# Generated by FakeRAM 2.0
VERSION 5.7 ;
BUSBITCHARS "[]" ;
PROPERTYDEFINITIONS
  MACRO width INTEGER ;
  MACRO depth INTEGER ;
  MACRO banks INTEGER ;
END PROPERTYDEFINITIONS
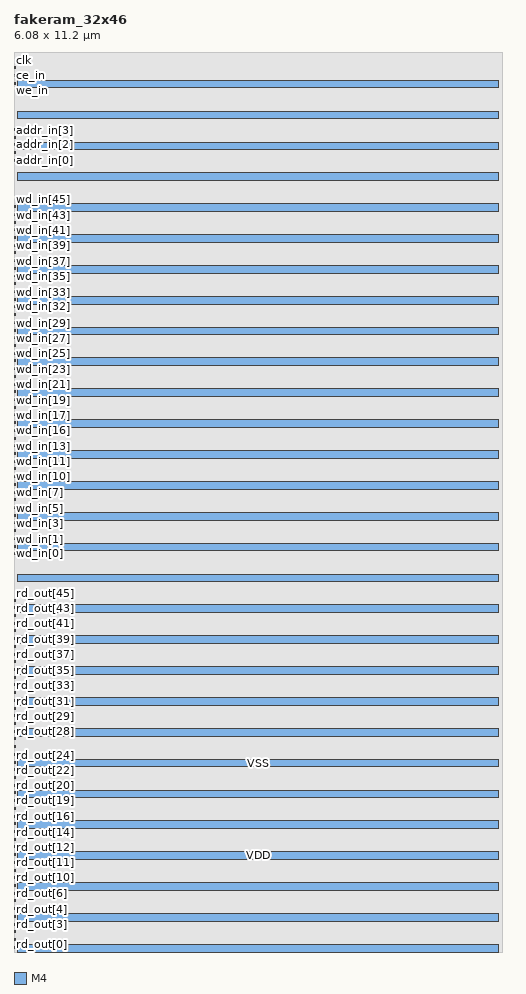
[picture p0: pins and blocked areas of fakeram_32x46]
MACRO fakeram_32x46
  PROPERTY width 46 ;
  PROPERTY depth 32 ;
  PROPERTY banks 1 ;
  FOREIGN fakeram_32x46 0 0 ;
  SYMMETRY X Y R90 ;
  SIZE 6.080 BY 11.200 ;
  CLASS BLOCK ;
  PIN rd_out[0]
    DIRECTION OUTPUT ;
    USE SIGNAL ;
    SHAPE ABUTMENT ;
    PORT
      LAYER M4 ;
      RECT 0.000 0.048 0.024 0.072 ;
    END
  END rd_out[0]
  PIN rd_out[1]
    DIRECTION OUTPUT ;
    USE SIGNAL ;
    SHAPE ABUTMENT ;
    PORT
      LAYER M4 ;
      RECT 0.000 0.144 0.024 0.168 ;
    END
  END rd_out[1]
  PIN rd_out[2]
    DIRECTION OUTPUT ;
    USE SIGNAL ;
    SHAPE ABUTMENT ;
    PORT
      LAYER M4 ;
      RECT 0.000 0.240 0.024 0.264 ;
    END
  END rd_out[2]
  PIN rd_out[3]
    DIRECTION OUTPUT ;
    USE SIGNAL ;
    SHAPE ABUTMENT ;
    PORT
      LAYER M4 ;
      RECT 0.000 0.336 0.024 0.360 ;
    END
  END rd_out[3]
  PIN rd_out[4]
    DIRECTION OUTPUT ;
    USE SIGNAL ;
    SHAPE ABUTMENT ;
    PORT
      LAYER M4 ;
      RECT 0.000 0.432 0.024 0.456 ;
    END
  END rd_out[4]
  PIN rd_out[5]
    DIRECTION OUTPUT ;
    USE SIGNAL ;
    SHAPE ABUTMENT ;
    PORT
      LAYER M4 ;
      RECT 0.000 0.528 0.024 0.552 ;
    END
  END rd_out[5]
  PIN rd_out[6]
    DIRECTION OUTPUT ;
    USE SIGNAL ;
    SHAPE ABUTMENT ;
    PORT
      LAYER M4 ;
      RECT 0.000 0.624 0.024 0.648 ;
    END
  END rd_out[6]
  PIN rd_out[7]
    DIRECTION OUTPUT ;
    USE SIGNAL ;
    SHAPE ABUTMENT ;
    PORT
      LAYER M4 ;
      RECT 0.000 0.720 0.024 0.744 ;
    END
  END rd_out[7]
  PIN rd_out[8]
    DIRECTION OUTPUT ;
    USE SIGNAL ;
    SHAPE ABUTMENT ;
    PORT
      LAYER M4 ;
      RECT 0.000 0.816 0.024 0.840 ;
    END
  END rd_out[8]
  PIN rd_out[9]
    DIRECTION OUTPUT ;
    USE SIGNAL ;
    SHAPE ABUTMENT ;
    PORT
      LAYER M4 ;
      RECT 0.000 0.912 0.024 0.936 ;
    END
  END rd_out[9]
  PIN rd_out[10]
    DIRECTION OUTPUT ;
    USE SIGNAL ;
    SHAPE ABUTMENT ;
    PORT
      LAYER M4 ;
      RECT 0.000 1.008 0.024 1.032 ;
    END
  END rd_out[10]
  PIN rd_out[11]
    DIRECTION OUTPUT ;
    USE SIGNAL ;
    SHAPE ABUTMENT ;
    PORT
      LAYER M4 ;
      RECT 0.000 1.104 0.024 1.128 ;
    END
  END rd_out[11]
  PIN rd_out[12]
    DIRECTION OUTPUT ;
    USE SIGNAL ;
    SHAPE ABUTMENT ;
    PORT
      LAYER M4 ;
      RECT 0.000 1.200 0.024 1.224 ;
    END
  END rd_out[12]
  PIN rd_out[13]
    DIRECTION OUTPUT ;
    USE SIGNAL ;
    SHAPE ABUTMENT ;
    PORT
      LAYER M4 ;
      RECT 0.000 1.296 0.024 1.320 ;
    END
  END rd_out[13]
  PIN rd_out[14]
    DIRECTION OUTPUT ;
    USE SIGNAL ;
    SHAPE ABUTMENT ;
    PORT
      LAYER M4 ;
      RECT 0.000 1.392 0.024 1.416 ;
    END
  END rd_out[14]
  PIN rd_out[15]
    DIRECTION OUTPUT ;
    USE SIGNAL ;
    SHAPE ABUTMENT ;
    PORT
      LAYER M4 ;
      RECT 0.000 1.488 0.024 1.512 ;
    END
  END rd_out[15]
  PIN rd_out[16]
    DIRECTION OUTPUT ;
    USE SIGNAL ;
    SHAPE ABUTMENT ;
    PORT
      LAYER M4 ;
      RECT 0.000 1.584 0.024 1.608 ;
    END
  END rd_out[16]
  PIN rd_out[17]
    DIRECTION OUTPUT ;
    USE SIGNAL ;
    SHAPE ABUTMENT ;
    PORT
      LAYER M4 ;
      RECT 0.000 1.680 0.024 1.704 ;
    END
  END rd_out[17]
  PIN rd_out[18]
    DIRECTION OUTPUT ;
    USE SIGNAL ;
    SHAPE ABUTMENT ;
    PORT
      LAYER M4 ;
      RECT 0.000 1.776 0.024 1.800 ;
    END
  END rd_out[18]
  PIN rd_out[19]
    DIRECTION OUTPUT ;
    USE SIGNAL ;
    SHAPE ABUTMENT ;
    PORT
      LAYER M4 ;
      RECT 0.000 1.872 0.024 1.896 ;
    END
  END rd_out[19]
  PIN rd_out[20]
    DIRECTION OUTPUT ;
    USE SIGNAL ;
    SHAPE ABUTMENT ;
    PORT
      LAYER M4 ;
      RECT 0.000 1.968 0.024 1.992 ;
    END
  END rd_out[20]
  PIN rd_out[21]
    DIRECTION OUTPUT ;
    USE SIGNAL ;
    SHAPE ABUTMENT ;
    PORT
      LAYER M4 ;
      RECT 0.000 2.064 0.024 2.088 ;
    END
  END rd_out[21]
  PIN rd_out[22]
    DIRECTION OUTPUT ;
    USE SIGNAL ;
    SHAPE ABUTMENT ;
    PORT
      LAYER M4 ;
      RECT 0.000 2.160 0.024 2.184 ;
    END
  END rd_out[22]
  PIN rd_out[23]
    DIRECTION OUTPUT ;
    USE SIGNAL ;
    SHAPE ABUTMENT ;
    PORT
      LAYER M4 ;
      RECT 0.000 2.256 0.024 2.280 ;
    END
  END rd_out[23]
  PIN rd_out[24]
    DIRECTION OUTPUT ;
    USE SIGNAL ;
    SHAPE ABUTMENT ;
    PORT
      LAYER M4 ;
      RECT 0.000 2.352 0.024 2.376 ;
    END
  END rd_out[24]
  PIN rd_out[25]
    DIRECTION OUTPUT ;
    USE SIGNAL ;
    SHAPE ABUTMENT ;
    PORT
      LAYER M4 ;
      RECT 0.000 2.448 0.024 2.472 ;
    END
  END rd_out[25]
  PIN rd_out[26]
    DIRECTION OUTPUT ;
    USE SIGNAL ;
    SHAPE ABUTMENT ;
    PORT
      LAYER M4 ;
      RECT 0.000 2.544 0.024 2.568 ;
    END
  END rd_out[26]
  PIN rd_out[27]
    DIRECTION OUTPUT ;
    USE SIGNAL ;
    SHAPE ABUTMENT ;
    PORT
      LAYER M4 ;
      RECT 0.000 2.640 0.024 2.664 ;
    END
  END rd_out[27]
  PIN rd_out[28]
    DIRECTION OUTPUT ;
    USE SIGNAL ;
    SHAPE ABUTMENT ;
    PORT
      LAYER M4 ;
      RECT 0.000 2.736 0.024 2.760 ;
    END
  END rd_out[28]
  PIN rd_out[29]
    DIRECTION OUTPUT ;
    USE SIGNAL ;
    SHAPE ABUTMENT ;
    PORT
      LAYER M4 ;
      RECT 0.000 2.832 0.024 2.856 ;
    END
  END rd_out[29]
  PIN rd_out[30]
    DIRECTION OUTPUT ;
    USE SIGNAL ;
    SHAPE ABUTMENT ;
    PORT
      LAYER M4 ;
      RECT 0.000 2.928 0.024 2.952 ;
    END
  END rd_out[30]
  PIN rd_out[31]
    DIRECTION OUTPUT ;
    USE SIGNAL ;
    SHAPE ABUTMENT ;
    PORT
      LAYER M4 ;
      RECT 0.000 3.024 0.024 3.048 ;
    END
  END rd_out[31]
  PIN rd_out[32]
    DIRECTION OUTPUT ;
    USE SIGNAL ;
    SHAPE ABUTMENT ;
    PORT
      LAYER M4 ;
      RECT 0.000 3.120 0.024 3.144 ;
    END
  END rd_out[32]
  PIN rd_out[33]
    DIRECTION OUTPUT ;
    USE SIGNAL ;
    SHAPE ABUTMENT ;
    PORT
      LAYER M4 ;
      RECT 0.000 3.216 0.024 3.240 ;
    END
  END rd_out[33]
  PIN rd_out[34]
    DIRECTION OUTPUT ;
    USE SIGNAL ;
    SHAPE ABUTMENT ;
    PORT
      LAYER M4 ;
      RECT 0.000 3.312 0.024 3.336 ;
    END
  END rd_out[34]
  PIN rd_out[35]
    DIRECTION OUTPUT ;
    USE SIGNAL ;
    SHAPE ABUTMENT ;
    PORT
      LAYER M4 ;
      RECT 0.000 3.408 0.024 3.432 ;
    END
  END rd_out[35]
  PIN rd_out[36]
    DIRECTION OUTPUT ;
    USE SIGNAL ;
    SHAPE ABUTMENT ;
    PORT
      LAYER M4 ;
      RECT 0.000 3.504 0.024 3.528 ;
    END
  END rd_out[36]
  PIN rd_out[37]
    DIRECTION OUTPUT ;
    USE SIGNAL ;
    SHAPE ABUTMENT ;
    PORT
      LAYER M4 ;
      RECT 0.000 3.600 0.024 3.624 ;
    END
  END rd_out[37]
  PIN rd_out[38]
    DIRECTION OUTPUT ;
    USE SIGNAL ;
    SHAPE ABUTMENT ;
    PORT
      LAYER M4 ;
      RECT 0.000 3.696 0.024 3.720 ;
    END
  END rd_out[38]
  PIN rd_out[39]
    DIRECTION OUTPUT ;
    USE SIGNAL ;
    SHAPE ABUTMENT ;
    PORT
      LAYER M4 ;
      RECT 0.000 3.792 0.024 3.816 ;
    END
  END rd_out[39]
  PIN rd_out[40]
    DIRECTION OUTPUT ;
    USE SIGNAL ;
    SHAPE ABUTMENT ;
    PORT
      LAYER M4 ;
      RECT 0.000 3.888 0.024 3.912 ;
    END
  END rd_out[40]
  PIN rd_out[41]
    DIRECTION OUTPUT ;
    USE SIGNAL ;
    SHAPE ABUTMENT ;
    PORT
      LAYER M4 ;
      RECT 0.000 3.984 0.024 4.008 ;
    END
  END rd_out[41]
  PIN rd_out[42]
    DIRECTION OUTPUT ;
    USE SIGNAL ;
    SHAPE ABUTMENT ;
    PORT
      LAYER M4 ;
      RECT 0.000 4.080 0.024 4.104 ;
    END
  END rd_out[42]
  PIN rd_out[43]
    DIRECTION OUTPUT ;
    USE SIGNAL ;
    SHAPE ABUTMENT ;
    PORT
      LAYER M4 ;
      RECT 0.000 4.176 0.024 4.200 ;
    END
  END rd_out[43]
  PIN rd_out[44]
    DIRECTION OUTPUT ;
    USE SIGNAL ;
    SHAPE ABUTMENT ;
    PORT
      LAYER M4 ;
      RECT 0.000 4.272 0.024 4.296 ;
    END
  END rd_out[44]
  PIN rd_out[45]
    DIRECTION OUTPUT ;
    USE SIGNAL ;
    SHAPE ABUTMENT ;
    PORT
      LAYER M4 ;
      RECT 0.000 4.368 0.024 4.392 ;
    END
  END rd_out[45]
  PIN wd_in[0]
    DIRECTION INPUT ;
    USE SIGNAL ;
    SHAPE ABUTMENT ;
    PORT
      LAYER M4 ;
      RECT 0.000 4.944 0.024 4.968 ;
    END
  END wd_in[0]
  PIN wd_in[1]
    DIRECTION INPUT ;
    USE SIGNAL ;
    SHAPE ABUTMENT ;
    PORT
      LAYER M4 ;
      RECT 0.000 5.040 0.024 5.064 ;
    END
  END wd_in[1]
  PIN wd_in[2]
    DIRECTION INPUT ;
    USE SIGNAL ;
    SHAPE ABUTMENT ;
    PORT
      LAYER M4 ;
      RECT 0.000 5.136 0.024 5.160 ;
    END
  END wd_in[2]
  PIN wd_in[3]
    DIRECTION INPUT ;
    USE SIGNAL ;
    SHAPE ABUTMENT ;
    PORT
      LAYER M4 ;
      RECT 0.000 5.232 0.024 5.256 ;
    END
  END wd_in[3]
  PIN wd_in[4]
    DIRECTION INPUT ;
    USE SIGNAL ;
    SHAPE ABUTMENT ;
    PORT
      LAYER M4 ;
      RECT 0.000 5.328 0.024 5.352 ;
    END
  END wd_in[4]
  PIN wd_in[5]
    DIRECTION INPUT ;
    USE SIGNAL ;
    SHAPE ABUTMENT ;
    PORT
      LAYER M4 ;
      RECT 0.000 5.424 0.024 5.448 ;
    END
  END wd_in[5]
  PIN wd_in[6]
    DIRECTION INPUT ;
    USE SIGNAL ;
    SHAPE ABUTMENT ;
    PORT
      LAYER M4 ;
      RECT 0.000 5.520 0.024 5.544 ;
    END
  END wd_in[6]
  PIN wd_in[7]
    DIRECTION INPUT ;
    USE SIGNAL ;
    SHAPE ABUTMENT ;
    PORT
      LAYER M4 ;
      RECT 0.000 5.616 0.024 5.640 ;
    END
  END wd_in[7]
  PIN wd_in[8]
    DIRECTION INPUT ;
    USE SIGNAL ;
    SHAPE ABUTMENT ;
    PORT
      LAYER M4 ;
      RECT 0.000 5.712 0.024 5.736 ;
    END
  END wd_in[8]
  PIN wd_in[9]
    DIRECTION INPUT ;
    USE SIGNAL ;
    SHAPE ABUTMENT ;
    PORT
      LAYER M4 ;
      RECT 0.000 5.808 0.024 5.832 ;
    END
  END wd_in[9]
  PIN wd_in[10]
    DIRECTION INPUT ;
    USE SIGNAL ;
    SHAPE ABUTMENT ;
    PORT
      LAYER M4 ;
      RECT 0.000 5.904 0.024 5.928 ;
    END
  END wd_in[10]
  PIN wd_in[11]
    DIRECTION INPUT ;
    USE SIGNAL ;
    SHAPE ABUTMENT ;
    PORT
      LAYER M4 ;
      RECT 0.000 6.000 0.024 6.024 ;
    END
  END wd_in[11]
  PIN wd_in[12]
    DIRECTION INPUT ;
    USE SIGNAL ;
    SHAPE ABUTMENT ;
    PORT
      LAYER M4 ;
      RECT 0.000 6.096 0.024 6.120 ;
    END
  END wd_in[12]
  PIN wd_in[13]
    DIRECTION INPUT ;
    USE SIGNAL ;
    SHAPE ABUTMENT ;
    PORT
      LAYER M4 ;
      RECT 0.000 6.192 0.024 6.216 ;
    END
  END wd_in[13]
  PIN wd_in[14]
    DIRECTION INPUT ;
    USE SIGNAL ;
    SHAPE ABUTMENT ;
    PORT
      LAYER M4 ;
      RECT 0.000 6.288 0.024 6.312 ;
    END
  END wd_in[14]
  PIN wd_in[15]
    DIRECTION INPUT ;
    USE SIGNAL ;
    SHAPE ABUTMENT ;
    PORT
      LAYER M4 ;
      RECT 0.000 6.384 0.024 6.408 ;
    END
  END wd_in[15]
  PIN wd_in[16]
    DIRECTION INPUT ;
    USE SIGNAL ;
    SHAPE ABUTMENT ;
    PORT
      LAYER M4 ;
      RECT 0.000 6.480 0.024 6.504 ;
    END
  END wd_in[16]
  PIN wd_in[17]
    DIRECTION INPUT ;
    USE SIGNAL ;
    SHAPE ABUTMENT ;
    PORT
      LAYER M4 ;
      RECT 0.000 6.576 0.024 6.600 ;
    END
  END wd_in[17]
  PIN wd_in[18]
    DIRECTION INPUT ;
    USE SIGNAL ;
    SHAPE ABUTMENT ;
    PORT
      LAYER M4 ;
      RECT 0.000 6.672 0.024 6.696 ;
    END
  END wd_in[18]
  PIN wd_in[19]
    DIRECTION INPUT ;
    USE SIGNAL ;
    SHAPE ABUTMENT ;
    PORT
      LAYER M4 ;
      RECT 0.000 6.768 0.024 6.792 ;
    END
  END wd_in[19]
  PIN wd_in[20]
    DIRECTION INPUT ;
    USE SIGNAL ;
    SHAPE ABUTMENT ;
    PORT
      LAYER M4 ;
      RECT 0.000 6.864 0.024 6.888 ;
    END
  END wd_in[20]
  PIN wd_in[21]
    DIRECTION INPUT ;
    USE SIGNAL ;
    SHAPE ABUTMENT ;
    PORT
      LAYER M4 ;
      RECT 0.000 6.960 0.024 6.984 ;
    END
  END wd_in[21]
  PIN wd_in[22]
    DIRECTION INPUT ;
    USE SIGNAL ;
    SHAPE ABUTMENT ;
    PORT
      LAYER M4 ;
      RECT 0.000 7.056 0.024 7.080 ;
    END
  END wd_in[22]
  PIN wd_in[23]
    DIRECTION INPUT ;
    USE SIGNAL ;
    SHAPE ABUTMENT ;
    PORT
      LAYER M4 ;
      RECT 0.000 7.152 0.024 7.176 ;
    END
  END wd_in[23]
  PIN wd_in[24]
    DIRECTION INPUT ;
    USE SIGNAL ;
    SHAPE ABUTMENT ;
    PORT
      LAYER M4 ;
      RECT 0.000 7.248 0.024 7.272 ;
    END
  END wd_in[24]
  PIN wd_in[25]
    DIRECTION INPUT ;
    USE SIGNAL ;
    SHAPE ABUTMENT ;
    PORT
      LAYER M4 ;
      RECT 0.000 7.344 0.024 7.368 ;
    END
  END wd_in[25]
  PIN wd_in[26]
    DIRECTION INPUT ;
    USE SIGNAL ;
    SHAPE ABUTMENT ;
    PORT
      LAYER M4 ;
      RECT 0.000 7.440 0.024 7.464 ;
    END
  END wd_in[26]
  PIN wd_in[27]
    DIRECTION INPUT ;
    USE SIGNAL ;
    SHAPE ABUTMENT ;
    PORT
      LAYER M4 ;
      RECT 0.000 7.536 0.024 7.560 ;
    END
  END wd_in[27]
  PIN wd_in[28]
    DIRECTION INPUT ;
    USE SIGNAL ;
    SHAPE ABUTMENT ;
    PORT
      LAYER M4 ;
      RECT 0.000 7.632 0.024 7.656 ;
    END
  END wd_in[28]
  PIN wd_in[29]
    DIRECTION INPUT ;
    USE SIGNAL ;
    SHAPE ABUTMENT ;
    PORT
      LAYER M4 ;
      RECT 0.000 7.728 0.024 7.752 ;
    END
  END wd_in[29]
  PIN wd_in[30]
    DIRECTION INPUT ;
    USE SIGNAL ;
    SHAPE ABUTMENT ;
    PORT
      LAYER M4 ;
      RECT 0.000 7.824 0.024 7.848 ;
    END
  END wd_in[30]
  PIN wd_in[31]
    DIRECTION INPUT ;
    USE SIGNAL ;
    SHAPE ABUTMENT ;
    PORT
      LAYER M4 ;
      RECT 0.000 7.920 0.024 7.944 ;
    END
  END wd_in[31]
  PIN wd_in[32]
    DIRECTION INPUT ;
    USE SIGNAL ;
    SHAPE ABUTMENT ;
    PORT
      LAYER M4 ;
      RECT 0.000 8.016 0.024 8.040 ;
    END
  END wd_in[32]
  PIN wd_in[33]
    DIRECTION INPUT ;
    USE SIGNAL ;
    SHAPE ABUTMENT ;
    PORT
      LAYER M4 ;
      RECT 0.000 8.112 0.024 8.136 ;
    END
  END wd_in[33]
  PIN wd_in[34]
    DIRECTION INPUT ;
    USE SIGNAL ;
    SHAPE ABUTMENT ;
    PORT
      LAYER M4 ;
      RECT 0.000 8.208 0.024 8.232 ;
    END
  END wd_in[34]
  PIN wd_in[35]
    DIRECTION INPUT ;
    USE SIGNAL ;
    SHAPE ABUTMENT ;
    PORT
      LAYER M4 ;
      RECT 0.000 8.304 0.024 8.328 ;
    END
  END wd_in[35]
  PIN wd_in[36]
    DIRECTION INPUT ;
    USE SIGNAL ;
    SHAPE ABUTMENT ;
    PORT
      LAYER M4 ;
      RECT 0.000 8.400 0.024 8.424 ;
    END
  END wd_in[36]
  PIN wd_in[37]
    DIRECTION INPUT ;
    USE SIGNAL ;
    SHAPE ABUTMENT ;
    PORT
      LAYER M4 ;
      RECT 0.000 8.496 0.024 8.520 ;
    END
  END wd_in[37]
  PIN wd_in[38]
    DIRECTION INPUT ;
    USE SIGNAL ;
    SHAPE ABUTMENT ;
    PORT
      LAYER M4 ;
      RECT 0.000 8.592 0.024 8.616 ;
    END
  END wd_in[38]
  PIN wd_in[39]
    DIRECTION INPUT ;
    USE SIGNAL ;
    SHAPE ABUTMENT ;
    PORT
      LAYER M4 ;
      RECT 0.000 8.688 0.024 8.712 ;
    END
  END wd_in[39]
  PIN wd_in[40]
    DIRECTION INPUT ;
    USE SIGNAL ;
    SHAPE ABUTMENT ;
    PORT
      LAYER M4 ;
      RECT 0.000 8.784 0.024 8.808 ;
    END
  END wd_in[40]
  PIN wd_in[41]
    DIRECTION INPUT ;
    USE SIGNAL ;
    SHAPE ABUTMENT ;
    PORT
      LAYER M4 ;
      RECT 0.000 8.880 0.024 8.904 ;
    END
  END wd_in[41]
  PIN wd_in[42]
    DIRECTION INPUT ;
    USE SIGNAL ;
    SHAPE ABUTMENT ;
    PORT
      LAYER M4 ;
      RECT 0.000 8.976 0.024 9.000 ;
    END
  END wd_in[42]
  PIN wd_in[43]
    DIRECTION INPUT ;
    USE SIGNAL ;
    SHAPE ABUTMENT ;
    PORT
      LAYER M4 ;
      RECT 0.000 9.072 0.024 9.096 ;
    END
  END wd_in[43]
  PIN wd_in[44]
    DIRECTION INPUT ;
    USE SIGNAL ;
    SHAPE ABUTMENT ;
    PORT
      LAYER M4 ;
      RECT 0.000 9.168 0.024 9.192 ;
    END
  END wd_in[44]
  PIN wd_in[45]
    DIRECTION INPUT ;
    USE SIGNAL ;
    SHAPE ABUTMENT ;
    PORT
      LAYER M4 ;
      RECT 0.000 9.264 0.024 9.288 ;
    END
  END wd_in[45]
  PIN addr_in[0]
    DIRECTION INPUT ;
    USE SIGNAL ;
    SHAPE ABUTMENT ;
    PORT
      LAYER M4 ;
      RECT 0.000 9.840 0.024 9.864 ;
    END
  END addr_in[0]
  PIN addr_in[1]
    DIRECTION INPUT ;
    USE SIGNAL ;
    SHAPE ABUTMENT ;
    PORT
      LAYER M4 ;
      RECT 0.000 9.936 0.024 9.960 ;
    END
  END addr_in[1]
  PIN addr_in[2]
    DIRECTION INPUT ;
    USE SIGNAL ;
    SHAPE ABUTMENT ;
    PORT
      LAYER M4 ;
      RECT 0.000 10.032 0.024 10.056 ;
    END
  END addr_in[2]
  PIN addr_in[3]
    DIRECTION INPUT ;
    USE SIGNAL ;
    SHAPE ABUTMENT ;
    PORT
      LAYER M4 ;
      RECT 0.000 10.128 0.024 10.152 ;
    END
  END addr_in[3]
  PIN addr_in[4]
    DIRECTION INPUT ;
    USE SIGNAL ;
    SHAPE ABUTMENT ;
    PORT
      LAYER M4 ;
      RECT 0.000 10.224 0.024 10.248 ;
    END
  END addr_in[4]
  PIN we_in
    DIRECTION INPUT ;
    USE SIGNAL ;
    SHAPE ABUTMENT ;
    PORT
      LAYER M4 ;
      RECT 0.000 10.800 0.024 10.824 ;
    END
  END we_in
  PIN ce_in
    DIRECTION INPUT ;
    USE SIGNAL ;
    SHAPE ABUTMENT ;
    PORT
      LAYER M4 ;
      RECT 0.000 10.896 0.024 10.920 ;
    END
  END ce_in
  PIN clk
    DIRECTION INPUT ;
    USE SIGNAL ;
    SHAPE ABUTMENT ;
    PORT
      LAYER M4 ;
      RECT 0.000 10.992 0.024 11.016 ;
    END
  END clk
  PIN VSS
    DIRECTION INOUT ;
    USE GROUND ;
    PORT
      LAYER M4 ;
      RECT 0.048 0.000 6.032 0.096 ;
      RECT 0.048 0.768 6.032 0.864 ;
      RECT 0.048 1.536 6.032 1.632 ;
      RECT 0.048 2.304 6.032 2.400 ;
      RECT 0.048 3.072 6.032 3.168 ;
      RECT 0.048 3.840 6.032 3.936 ;
      RECT 0.048 4.608 6.032 4.704 ;
      RECT 0.048 5.376 6.032 5.472 ;
      RECT 0.048 6.144 6.032 6.240 ;
      RECT 0.048 6.912 6.032 7.008 ;
      RECT 0.048 7.680 6.032 7.776 ;
      RECT 0.048 8.448 6.032 8.544 ;
      RECT 0.048 9.216 6.032 9.312 ;
      RECT 0.048 9.984 6.032 10.080 ;
      RECT 0.048 10.752 6.032 10.848 ;
    END
  END VSS
  PIN VDD
    DIRECTION INOUT ;
    USE POWER ;
    PORT
      LAYER M4 ;
      RECT 0.048 0.384 6.032 0.480 ;
      RECT 0.048 1.152 6.032 1.248 ;
      RECT 0.048 1.920 6.032 2.016 ;
      RECT 0.048 2.688 6.032 2.784 ;
      RECT 0.048 3.456 6.032 3.552 ;
      RECT 0.048 4.224 6.032 4.320 ;
      RECT 0.048 4.992 6.032 5.088 ;
      RECT 0.048 5.760 6.032 5.856 ;
      RECT 0.048 6.528 6.032 6.624 ;
      RECT 0.048 7.296 6.032 7.392 ;
      RECT 0.048 8.064 6.032 8.160 ;
      RECT 0.048 8.832 6.032 8.928 ;
      RECT 0.048 9.600 6.032 9.696 ;
      RECT 0.048 10.368 6.032 10.464 ;
    END
  END VDD
  OBS
    LAYER M1 ;
    RECT 0 0 6.080 11.200 ;
    LAYER M2 ;
    RECT 0 0 6.080 11.200 ;
    LAYER M3 ;
    RECT 0 0 6.080 11.200 ;
    LAYER M4 ;
    RECT 0 0 6.080 11.200 ;
  END
END fakeram_32x46

END LIBRARY
